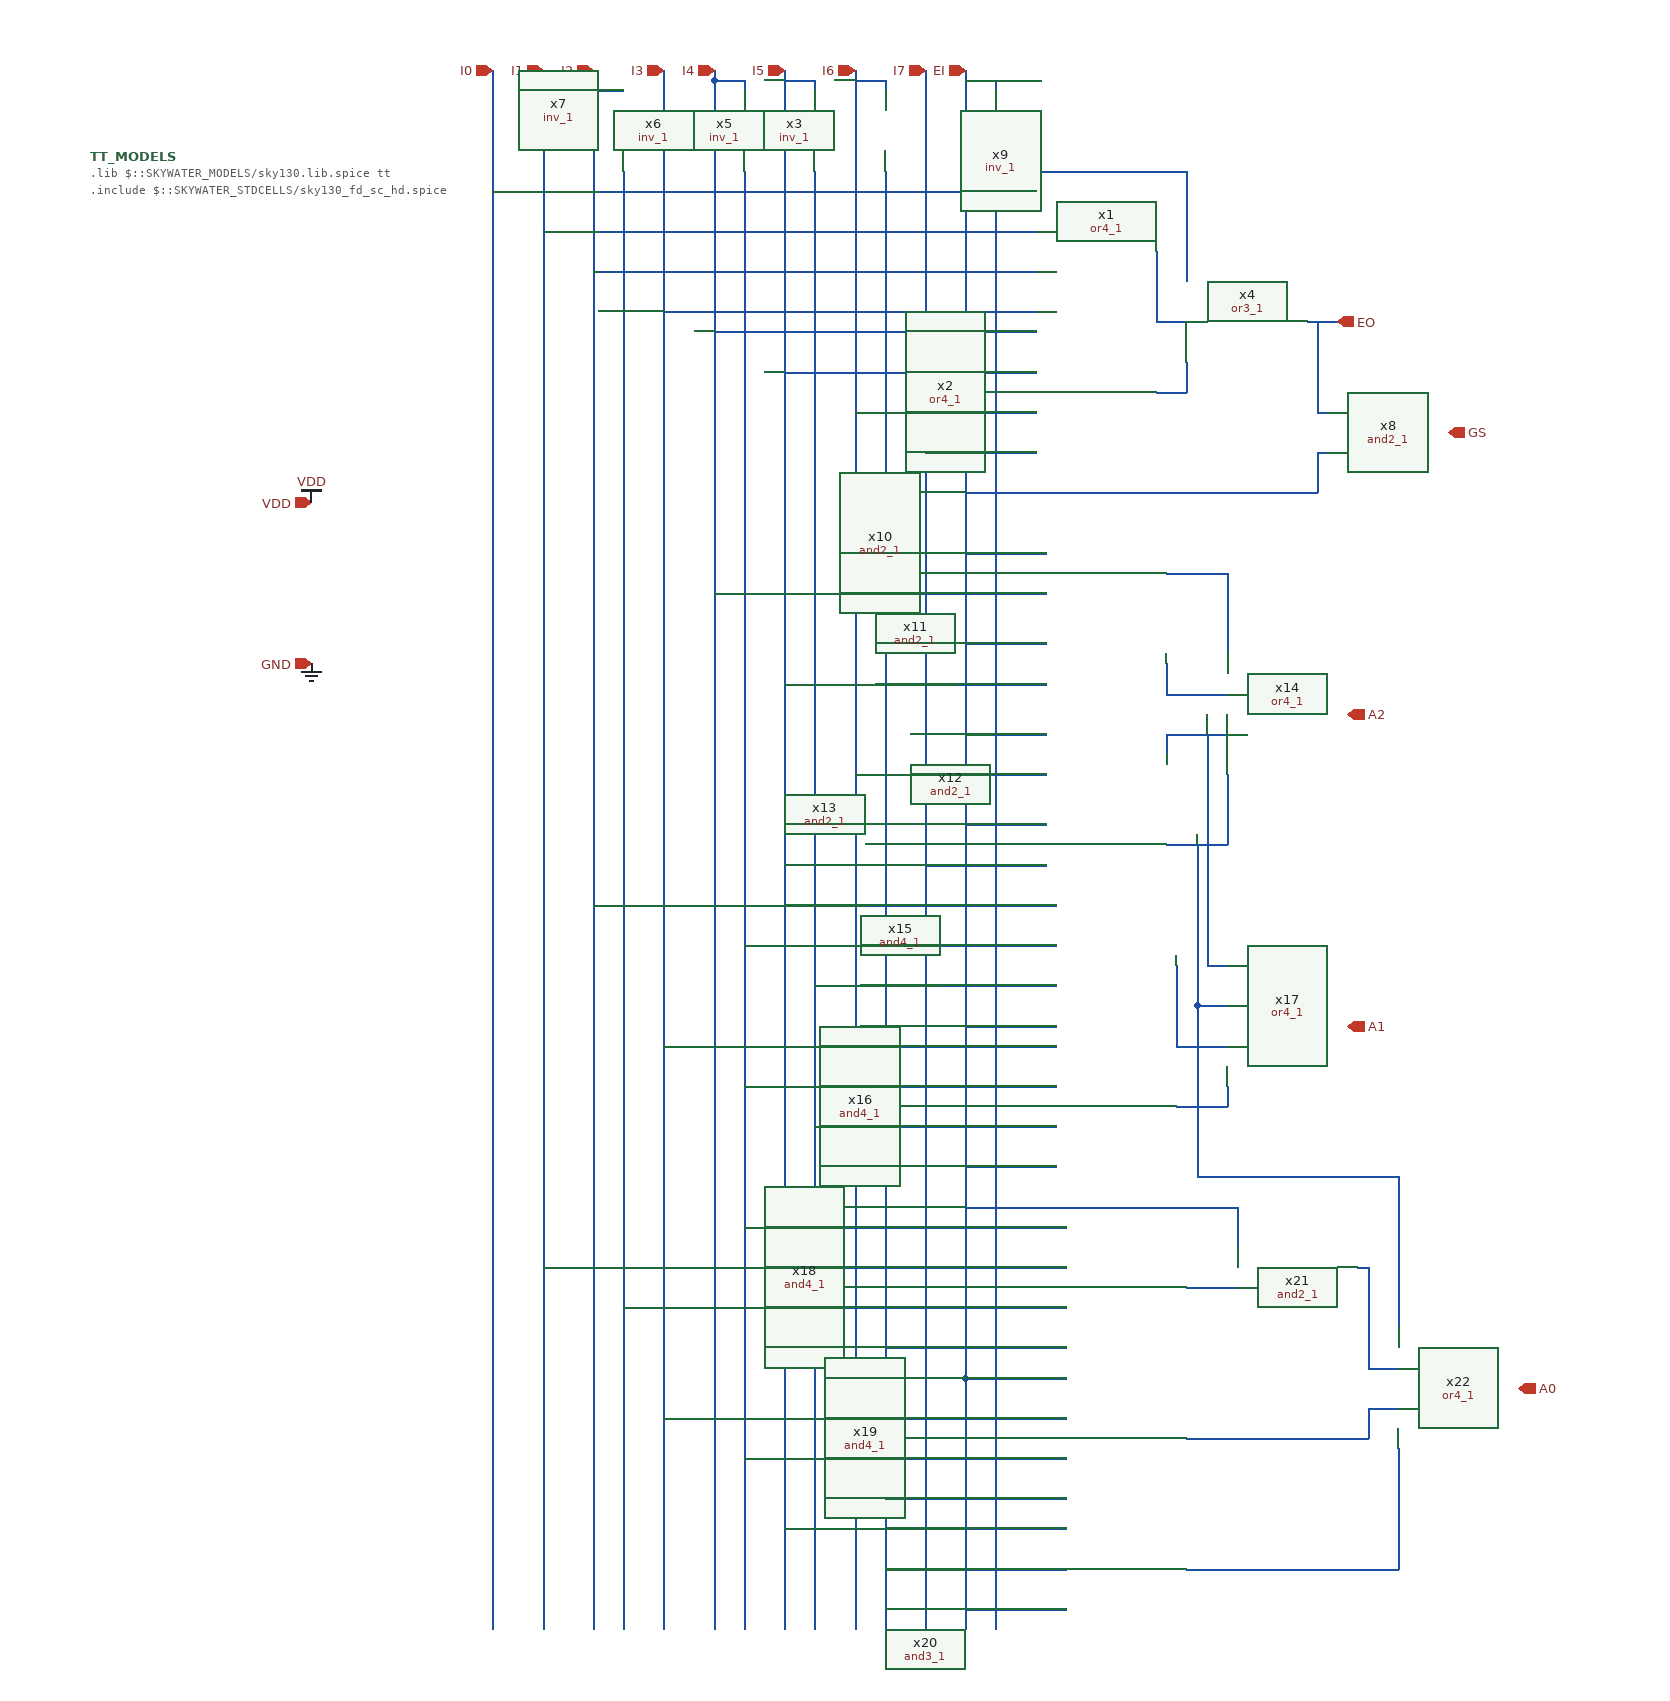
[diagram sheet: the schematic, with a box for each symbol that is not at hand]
v {xschem version=3.4.5 file_version=1.2
}
G {}
K {}
V {}
S {}
E {}
N -290 -160 -290 -140 {
lab=I0}
N -290 -140 -290 490 {
lab=I0}
N -190 -160 -190 -140 {
lab=I2}
N -190 -140 -180 -140 {
lab=I2}
N -180 -140 -160 -140 {
lab=I2}
N -120 -160 -120 490 {
lab=I3}
N -160 -60 -160 480 {
lab=#net1}
N -160 480 -160 490 {
lab=#net1}
N -190 -140 -190 490 {
lab=I2}
N -70 -150 -70 490 {
lab=I4}
N -40 -60 -40 490 {
lab=#net2}
N -70 -160 -70 -150 {
lab=I4}
N -70 -150 -40 -150 {
lab=I4}
N -40 -150 -40 -140 {
lab=I4}
N 0 -160 0 490 {
lab=I5}
N 0 -150 30 -150 {
lab=I5}
N 30 -150 30 -140 {
lab=I5}
N 30 -60 30 480 {
lab=#net3}
N 30 480 30 490 {
lab=#net3}
N 70 -160 70 490 {
lab=I6}
N 70 -150 100 -150 {
lab=I6}
N 100 -150 100 -140 {
lab=I6}
N 100 -60 100 490 {
lab=#net4}
N 140 -160 140 490 {
lab=I7}
N 180 -160 180 480 {
lab=EI}
N 180 480 180 490 {
lab=EI}
N 180 -150 210 -150 {
lab=EI}
N 210 -150 210 -140 {
lab=EI}
N 210 -60 210 490 {
lab=#net5}
N -240 -160 -240 490 {
lab=I1}
N -290 510 -290 1140 {
lab=I0}
N -120 490 -120 1140 {
lab=I3}
N -160 590 -160 1130 {
lab=#net1}
N -160 1130 -160 1140 {
lab=#net1}
N -190 510 -190 1140 {
lab=I2}
N -70 500 -70 1140 {
lab=I4}
N -40 590 -40 1140 {
lab=#net2}
N 0 490 0 1140 {
lab=I5}
N 30 590 30 1130 {
lab=#net3}
N 30 1130 30 1140 {
lab=#net3}
N 70 490 70 1140 {
lab=I6}
N 100 590 100 1140 {
lab=#net4}
N 140 490 140 1140 {
lab=I7}
N 180 490 180 1130 {
lab=EI}
N 180 1130 180 1140 {
lab=EI}
N -240 490 -240 1140 {
lab=I1}
N -290 490 -290 510 {
lab=I0}
N -190 490 -190 510 {
lab=I2}
N -70 490 -70 500 {
lab=I4}
N -160 490 -160 590 {
lab=#net1}
N -40 490 -40 590 {
lab=#net2}
N 30 490 30 590 {
lab=#net3}
N 100 490 100 590 {
lab=#net4}
N -290 -40 250 -40 {
lab=I0}
N -240 0 250 0 {
lab=I1}
N -190 40 250 40 {
lab=I2}
N -120 80 250 80 {
lab=I3}
N -70 100 250 100 {
lab=I4}
N 0 140 250 140 {
lab=I5}
N 70 180 250 180 {
lab=I6}
N 140 220 250 220 {
lab=I7}
N 370 160 400 160 {
lab=#net6}
N 400 140 400 160 {
lab=#net6}
N 400 130 400 140 {
lab=#net6}
N 370 20 370 90 {
lab=#net7}
N 370 90 400 90 {
lab=#net7}
N 210 -60 400 -60 {
lab=#net5}
N 400 -60 400 50 {
lab=#net5}
N 520 90 550 90 {
lab=EO}
N 530 220 530 250 {
lab=EI}
N 180 260 530 260 {
lab=EI}
N 530 250 530 260 {
lab=EI}
N 530 220 540 220 {
lab=EI}
N 530 90 530 180 {
lab=EO}
N 530 180 540 180 {
lab=EO}
N 180 320 260 320 {
lab=EI}
N -70 360 260 360 {
lab=I4}
N 180 410 260 410 {
lab=EI}
N 180 500 260 500 {
lab=EI}
N 180 590 260 590 {
lab=EI}
N 0 450 260 450 {
lab=I5}
N 70 540 260 540 {
lab=I6}
N 140 630 260 630 {
lab=I7}
N 380 340 440 340 {
lab=#net8}
N 380 430 380 460 {
lab=#net9}
N 400 460 440 460 {
lab=#net9}
N 380 460 400 460 {
lab=#net9}
N 440 340 440 420 {
lab=#net8}
N 380 500 380 520 {
lab=#net10}
N 380 500 440 500 {
lab=#net10}
N 380 610 440 610 {
lab=#net11}
N 440 540 440 610 {
lab=#net11}
N 390 870 440 870 {
lab=#net12}
N 440 850 440 870 {
lab=#net12}
N 390 730 390 810 {
lab=#net13}
N 390 810 440 810 {
lab=#net13}
N 410 610 410 770 {
lab=#net11}
N 410 770 440 770 {
lab=#net11}
N 430 730 440 730 {
lab=#net10}
N 420 500 420 730 {
lab=#net10}
N 420 730 430 730 {
lab=#net10}
N -180 670 270 670 {
lab=I2}
N -190 670 -180 670 {
lab=I2}
N -40 710 270 710 {
lab=#net2}
N 30 750 270 750 {
lab=#net3}
N 180 790 270 790 {
lab=EI}
N 180 930 270 930 {
lab=EI}
N 30 890 270 890 {
lab=#net3}
N -40 850 270 850 {
lab=I5}
N -110 810 270 810 {
lab=I3}
N -120 810 -110 810 {
lab=I3}
N 180 1140 180 1390 {
lab=EI}
N 140 1140 140 1380 {
lab=I7}
N 100 1140 100 1390 {
lab=#net4}
N 140 1380 140 1390 {
lab=I7}
N 70 1140 70 1390 {
lab=I6}
N 30 1140 30 1390 {
lab=#net3}
N 0 1140 0 1380 {
lab=I5}
N -0 1380 0 1390 {
lab=I5}
N -40 1140 -40 1390 {
lab=#net2}
N -70 1140 -70 1390 {
lab=I4}
N -120 1140 -120 1390 {
lab=I3}
N -160 1140 -160 1390 {
lab=#net1}
N -190 1140 -190 1390 {
lab=I2}
N -240 1140 -240 1390 {
lab=I1}
N -290 1140 -290 1390 {
lab=I0}
N 180 970 450 970 {
lab=EI}
N 450 970 450 1010 {
lab=EI}
N 400 1050 450 1050 {
lab=#net14}
N -30 990 280 990 {
lab=#net2}
N -40 990 -30 990 {
lab=#net2}
N -240 1030 280 1030 {
lab=I1}
N -160 1070 280 1070 {
lab=#net1}
N 100 1110 280 1110 {
lab=#net4}
N 180 1140 280 1140 {
lab=EI}
N 210 490 210 1390 {
lab=#net5}
N -120 1180 280 1180 {
lab=I3}
N -40 1220 280 1220 {
lab=#net2}
N 100 1260 280 1260 {
lab=#net4}
N 0 1290 280 1290 {
lab=I5}
N 100 1330 280 1330 {
lab=#net4}
N 180 1370 280 1370 {
lab=EI}
N 410 770 410 940 {
lab=#net11}
N 410 940 610 940 {
lab=#net11}
N 610 940 610 1090 {
lab=#net11}
N 400 1200 580 1200 {
lab=#net15}
N 580 1170 580 1200 {
lab=#net15}
N 580 1170 610 1170 {
lab=#net15}
N 570 1030 580 1030 {
lab=#net16}
N 580 1030 580 1130 {
lab=#net16}
N 580 1130 610 1130 {
lab=#net16}
N 400 1330 610 1330 {
lab=#net17}
N 610 1210 610 1330 {
lab=#net17}
C {devices/code.sym} -690 -75 0 0 {name=TT_MODELS
only_toplevel=true
format="tcleval(@value )"
value=".lib $::SKYWATER_MODELS/sky130.lib.spice tt
.include $::SKYWATER_STDCELLS/sky130_fd_sc_hd.spice
"
spice_ignore=false
place=header}
C {devices/ipin.sym} -290 -160 1 0 {name=p1 lab=I0}
C {devices/ipin.sym} -240 -160 1 0 {name=p2 lab=I1}
C {devices/ipin.sym} -190 -160 1 0 {name=p3 lab=I2}
C {devices/ipin.sym} -120 -160 1 0 {name=p4 lab=I3}
C {devices/ipin.sym} -70 -160 1 0 {name=p5 lab=I4}
C {devices/ipin.sym} 0 -160 1 0 {name=p6 lab=I5}
C {devices/ipin.sym} 70 -160 1 0 {name=p7 lab=I6}
C {devices/ipin.sym} 140 -160 1 0 {name=p8 lab=I7}
C {devices/ipin.sym} 180 -160 1 0 {name=p9 lab=EI}
C {sky130_stdcells/inv_1.sym} 210 -100 1 0 {name=x9 VGND=GND VNB=GND VPB=VDD VPWR=VDD prefix=sky130_fd_sc_hd__ }
C {sky130_stdcells/or4_1.sym} 310 20 0 0 {name=x1 VGND=GND VNB=GND VPB=VDD VPWR=VDD prefix=sky130_fd_sc_hd__ }
C {sky130_stdcells/or4_1.sym} 310 160 0 0 {name=x2 VGND=GND VNB=GND VPB=VDD VPWR=VDD prefix=sky130_fd_sc_hd__ }
C {sky130_stdcells/or3_1.sym} 460 90 0 0 {name=x4 VGND=GND VNB=GND VPB=VDD VPWR=VDD prefix=sky130_fd_sc_hd__ }
C {devices/opin.sym} 550 90 0 0 {name=p10 lab=EO}
C {sky130_stdcells/and2_1.sym} 600 200 0 0 {name=x8 VGND=GND VNB=GND VPB=VDD VPWR=VDD prefix=sky130_fd_sc_hd__ }
C {devices/opin.sym} 660 200 0 0 {name=p11 lab=GS}
C {sky130_stdcells/and2_1.sym} 320 340 0 0 {name=x10 VGND=GND VNB=GND VPB=VDD VPWR=VDD prefix=sky130_fd_sc_hd__ }
C {sky130_stdcells/and2_1.sym} 320 430 0 0 {name=x11 VGND=GND VNB=GND VPB=VDD VPWR=VDD prefix=sky130_fd_sc_hd__ }
C {sky130_stdcells/and2_1.sym} 320 520 0 0 {name=x12 VGND=GND VNB=GND VPB=VDD VPWR=VDD prefix=sky130_fd_sc_hd__ }
C {sky130_stdcells/and2_1.sym} 320 610 0 0 {name=x13 VGND=GND VNB=GND VPB=VDD VPWR=VDD prefix=sky130_fd_sc_hd__ }
C {sky130_stdcells/or4_1.sym} 500 480 0 0 {name=x14 VGND=GND VNB=GND VPB=VDD VPWR=VDD prefix=sky130_fd_sc_hd__ }
C {devices/opin.sym} 560 480 0 0 {name=p12 lab=A2}
C {sky130_stdcells/or4_1.sym} 500 790 0 0 {name=x17 VGND=GND VNB=GND VPB=VDD VPWR=VDD prefix=sky130_fd_sc_hd__ }
C {devices/opin.sym} 560 790 0 0 {name=p13 lab=A1}
C {sky130_stdcells/and4_1.sym} 330 730 0 0 {name=x15 VGND=GND VNB=GND VPB=VDD VPWR=VDD prefix=sky130_fd_sc_hd__ }
C {sky130_stdcells/and4_1.sym} 330 870 0 0 {name=x16 VGND=GND VNB=GND VPB=VDD VPWR=VDD prefix=sky130_fd_sc_hd__ }
C {sky130_stdcells/and4_1.sym} 340 1050 0 0 {name=x18 VGND=GND VNB=GND VPB=VDD VPWR=VDD prefix=sky130_fd_sc_hd__ }
C {sky130_stdcells/and4_1.sym} 340 1200 0 0 {name=x19 VGND=GND VNB=GND VPB=VDD VPWR=VDD prefix=sky130_fd_sc_hd__ }
C {sky130_stdcells/and3_1.sym} 340 1330 0 0 {name=x20 VGND=GND VNB=GND VPB=VDD VPWR=VDD prefix=sky130_fd_sc_hd__ }
C {sky130_stdcells/and2_1.sym} 510 1030 0 0 {name=x21 VGND=GND VNB=GND VPB=VDD VPWR=VDD prefix=sky130_fd_sc_hd__ }
C {sky130_stdcells/or4_1.sym} 670 1150 0 0 {name=x22 VGND=GND VNB=GND VPB=VDD VPWR=VDD prefix=sky130_fd_sc_hd__ }
C {devices/opin.sym} 730 1150 0 0 {name=p14 lab=A0}
C {sky130_stdcells/inv_1.sym} 100 -100 1 0 {name=x3 VGND=GND VNB=GND VPB=VDD VPWR=VDD prefix=sky130_fd_sc_hd__ }
C {sky130_stdcells/inv_1.sym} 30 -100 1 0 {name=x5 VGND=GND VNB=GND VPB=VDD VPWR=VDD prefix=sky130_fd_sc_hd__ }
C {sky130_stdcells/inv_1.sym} -40 -100 1 0 {name=x6 VGND=GND VNB=GND VPB=VDD VPWR=VDD prefix=sky130_fd_sc_hd__ }
C {sky130_stdcells/inv_1.sym} -160 -100 1 0 {name=x7 VGND=GND VNB=GND VPB=VDD VPWR=VDD prefix=sky130_fd_sc_hd__ }
C {devices/ipin.sym} -470 270 2 0 {name=p15 lab=VDD}
C {devices/ipin.sym} -470 430 2 0 {name=p16 lab=GND}
C {devices/vdd.sym} -470 270 0 0 {name=l9 lab=VDD}
C {devices/gnd.sym} -470 430 0 1 {name=l13 lab=GND}
